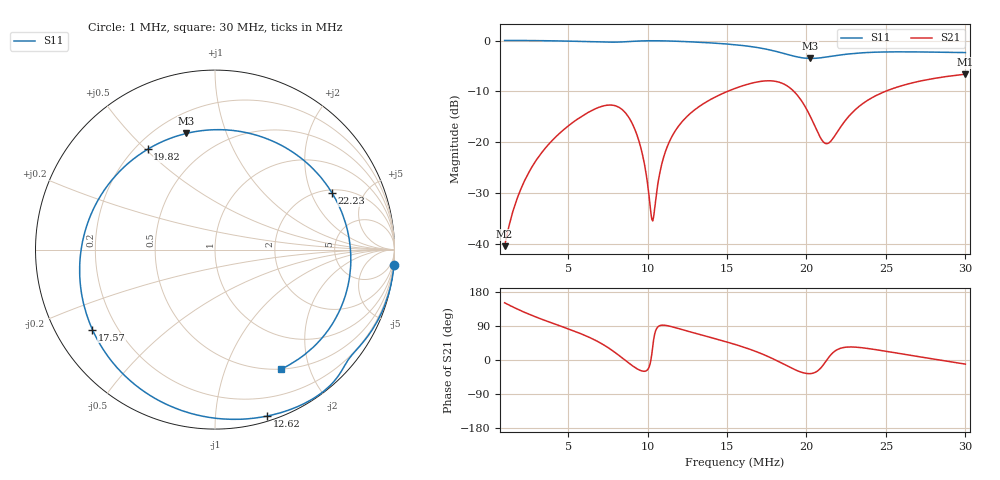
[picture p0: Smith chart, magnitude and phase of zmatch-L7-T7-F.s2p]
# HZ S RI R 50
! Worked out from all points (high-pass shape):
!   505 points, 1 MHz to 30 MHz, reference 50 ohm
!   highest |S21| = -6.63 dB at 30 MHz (marker M1); lowest = -40.4 dB at 1 MHz (marker M2)
!   |S21| within 3 dB of the highest: 15.32 MHz to 19.08 MHz (3.764 MHz wide, 21.9 % of centre); 25.26 MHz to end of sweep
!   lowest |S11| = -3.5 dB at 20.22 MHz (marker M3), VSWR 5.00, Z = 15.7 + j36.6 ohm
!   |S11| at or under -10 dB: nowhere
!   S12 and S22 are empty: the file has one direction only
!   S11 on the Smith chart (normalised r, x): 1 MHz: -0, -23; 12.62 MHz: 0.04, -1.36; 17.57 MHz: 0.11, -0.29; 19.82 MHz: 0.25, +0.51; 22.23 MHz: 2.16, +2.87; 30 MHz: 0.50, -1.58
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1000000  0.9972 -0.0884  -0.00835 0.00462  0 0  0 0
1748020  0.9888 -0.1531  -0.0192 0.0188  0 0  0 0
2726200  0.9701 -0.237  -0.0266 0.051  0 0  0 0
5833360  0.851 -0.4829  0.0648 0.167  0 0  0 0
8422660  0.7245 -0.6428  0.2074 0.0169  0 0  0 0
9515920  0.6615 -0.7361  0.085 -0.0434  0 0  0 0
1.026394e7  0.5912 -0.8002  0.0169 0.00474  0 0  0 0
1.037902e7  0.579 -0.8093  0.011 0.0149  0 0  0 0
1.066672e7  0.5468 -0.8302  0.00132 0.041  0 0  0 0
1.13572e7  0.4635 -0.8732  0.000668 0.1004  0 0  0 0
1.262308e7  0.29 -0.9276  0.0488 0.1817  0 0  0 0
1.550008e7  -0.2343 -0.8782  0.2548 0.2225  0 0  0 0
1.757152e7  -0.6831 -0.446  0.3968 0.0655  0 0  0 0
1.877986e7  -0.7234 0.1041  0.3454 -0.096  0 0  0 0
1.981558e7  -0.3753 0.5589  0.1973 -0.1329  0 0  0 0
2.021836e7  -0.1608 0.647  0.1477 -0.1072  0 0  0 0
2.033344e7  -0.0969 0.6596  0.1364 -0.0971  0 0  0 0
2.125408e7  0.366 0.5829  0.0969 -0.00252  0 0  0 0
2.223226e7  0.6527 0.3145  0.1253 0.0782  0 0  0 0
2.34406e7  0.7558 -0.017  0.1969 0.1258  0 0  0 0
2.51668e7  0.6956 -0.3364  0.3023 0.1216  0 0  0 0
3.000016e7  0.3693 -0.6656  0.4578 -0.0882  0 0  0 0
